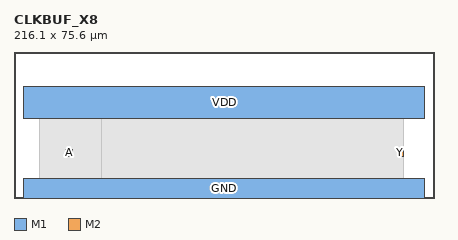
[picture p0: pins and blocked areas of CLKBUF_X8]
MACRO CLKBUF_X8
  CLASS CORE ;
  ORIGIN 0 0 ;
  SIZE 216.100 BY 75.600 ;
  SYMMETRY X Y ;
  SITE TR1um_access_site ;
  PIN VDD
    DIRECTION INOUT ;
    USE POWER ;
    PORT
      LAYER M1 ;
        RECT 5.000 41.000 211.100 57.600 ;
    END
  END VDD
  PIN GND
    DIRECTION INOUT ;
    USE GROUND ;
    PORT
      LAYER M1 ;
        RECT 5.000 0.000 211.100 9.800 ;
    END
  END GND
  PIN A
    DIRECTION INPUT ;
    USE SIGNAL ;
    PORT
      LAYER M2 ;
        RECT 26.600 21.600 30.000 25.000 ;
    END
  END A
  PIN Y
    DIRECTION OUTPUT ;
    USE SIGNAL ;
    PORT
      LAYER M2 ;
        RECT 197.100 21.600 200.500 25.000 ;
    END
  END Y
  OBS
    LAYER M1 ;
      RECT 17.100 16.400 35.700 34.400 ;
    LAYER M1 ;
      RECT 13.100 6.400 193.700 51.200 ;
    LAYER M1 ;
      RECT 45.100 6.400 200.500 51.200 ;
    LAYER V1 ;
      RECT 27.600 22.600 29.000 24.000 ;
    LAYER V1 ;
      RECT 198.100 22.600 199.500 24.000 ;
  END
END CLKBUF_X8
